VERSION 5.8 ;
BUSBITCHARS "[]" ;
DIVIDERCHAR "/" ;
UNITS
    DATABASE MICRONS 1000 ;
END UNITS

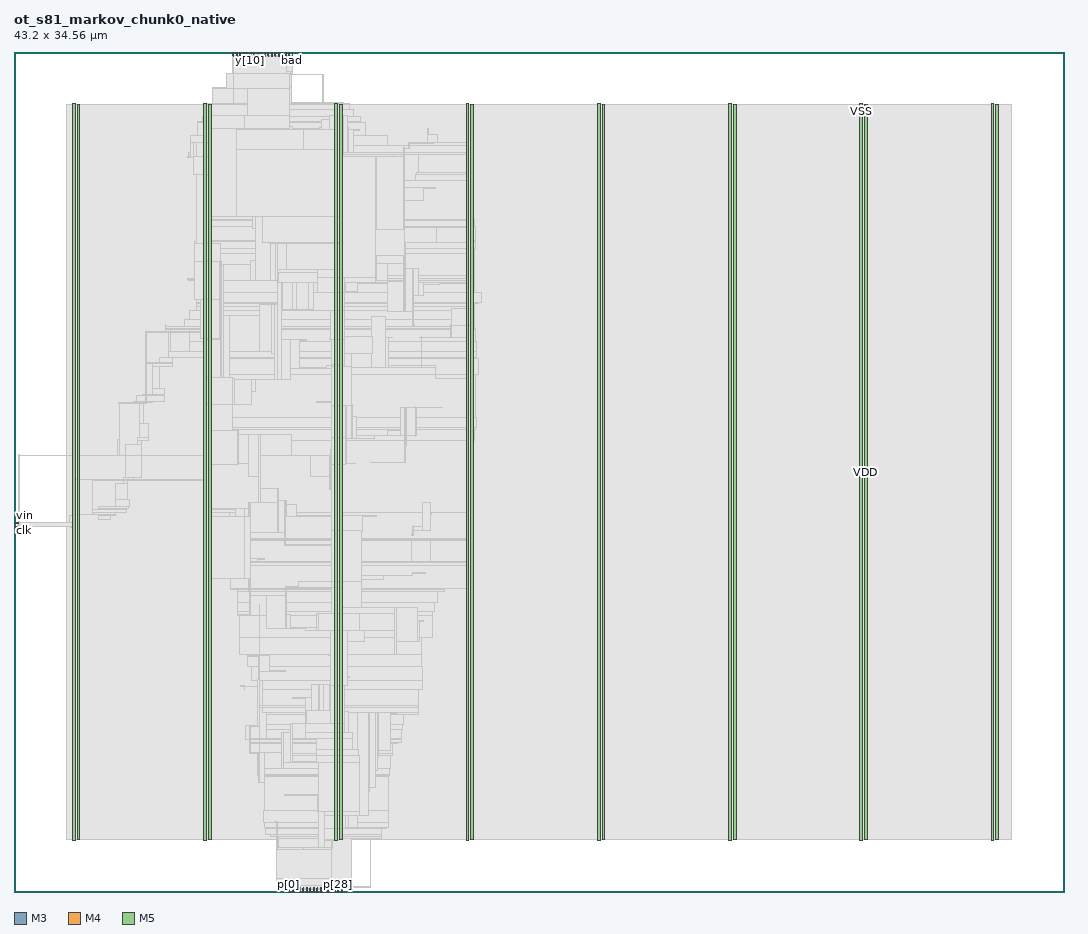
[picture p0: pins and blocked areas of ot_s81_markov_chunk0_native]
MACRO ot_s81_markov_chunk0_native
  FOREIGN ot_s81_markov_chunk0_native 0 0 ;
  CLASS BLOCK ;
  SIZE 43.2 BY 34.56 ;
  PIN bad
    DIRECTION OUTPUT ;
    USE SIGNAL ;
    PORT
      LAYER M3 ;
        RECT  11.448 34.416 11.466 34.56 ;
    END
  END bad
  PIN clk
    DIRECTION INPUT ;
    USE SIGNAL ;
    PORT
      LAYER M4 ;
        RECT  0 14.88 0.192 14.904 ;
    END
  END clk
  PIN p[0]
    DIRECTION INPUT ;
    USE SIGNAL ;
    PORT
      LAYER M3 ;
        RECT  11.304 0 11.322 0.144 ;
    END
  END p[0]
  PIN p[10]
    DIRECTION INPUT ;
    USE SIGNAL ;
    PORT
      LAYER M3 ;
        RECT  12.024 0 12.042 0.144 ;
    END
  END p[10]
  PIN p[11]
    DIRECTION INPUT ;
    USE SIGNAL ;
    PORT
      LAYER M5 ;
        RECT  12.048 0 12.072 0.192 ;
    END
  END p[11]
  PIN p[12]
    DIRECTION INPUT ;
    USE SIGNAL ;
    PORT
      LAYER M3 ;
        RECT  12.168 0 12.186 0.144 ;
    END
  END p[12]
  PIN p[13]
    DIRECTION INPUT ;
    USE SIGNAL ;
    PORT
      LAYER M5 ;
        RECT  12.192 0 12.216 0.192 ;
    END
  END p[13]
  PIN p[14]
    DIRECTION INPUT ;
    USE SIGNAL ;
    PORT
      LAYER M3 ;
        RECT  12.312 0 12.33 0.144 ;
    END
  END p[14]
  PIN p[15]
    DIRECTION INPUT ;
    USE SIGNAL ;
    PORT
      LAYER M5 ;
        RECT  12.336 0 12.36 0.192 ;
    END
  END p[15]
  PIN p[16]
    DIRECTION INPUT ;
    USE SIGNAL ;
    PORT
      LAYER M3 ;
        RECT  12.456 0 12.474 0.144 ;
    END
  END p[16]
  PIN p[17]
    DIRECTION INPUT ;
    USE SIGNAL ;
    PORT
      LAYER M5 ;
        RECT  12.48 0 12.504 0.192 ;
    END
  END p[17]
  PIN p[18]
    DIRECTION INPUT ;
    USE SIGNAL ;
    PORT
      LAYER M3 ;
        RECT  12.6 0 12.618 0.144 ;
    END
  END p[18]
  PIN p[19]
    DIRECTION INPUT ;
    USE SIGNAL ;
    PORT
      LAYER M5 ;
        RECT  12.624 0 12.648 0.192 ;
    END
  END p[19]
  PIN p[1]
    DIRECTION INPUT ;
    USE SIGNAL ;
    PORT
      LAYER M5 ;
        RECT  11.328 0 11.352 0.192 ;
    END
  END p[1]
  PIN p[20]
    DIRECTION INPUT ;
    USE SIGNAL ;
    PORT
      LAYER M3 ;
        RECT  12.744 0 12.762 0.144 ;
    END
  END p[20]
  PIN p[21]
    DIRECTION INPUT ;
    USE SIGNAL ;
    PORT
      LAYER M5 ;
        RECT  12.768 0 12.792 0.192 ;
    END
  END p[21]
  PIN p[22]
    DIRECTION INPUT ;
    USE SIGNAL ;
    PORT
      LAYER M3 ;
        RECT  12.888 0 12.906 0.144 ;
    END
  END p[22]
  PIN p[23]
    DIRECTION INPUT ;
    USE SIGNAL ;
    PORT
      LAYER M5 ;
        RECT  12.912 0 12.936 0.192 ;
    END
  END p[23]
  PIN p[24]
    DIRECTION INPUT ;
    USE SIGNAL ;
    PORT
      LAYER M3 ;
        RECT  13.032 0 13.05 0.144 ;
    END
  END p[24]
  PIN p[25]
    DIRECTION INPUT ;
    USE SIGNAL ;
    PORT
      LAYER M5 ;
        RECT  13.056 0 13.08 0.192 ;
    END
  END p[25]
  PIN p[26]
    DIRECTION INPUT ;
    USE SIGNAL ;
    PORT
      LAYER M3 ;
        RECT  13.176 0 13.194 0.144 ;
    END
  END p[26]
  PIN p[27]
    DIRECTION INPUT ;
    USE SIGNAL ;
    PORT
      LAYER M5 ;
        RECT  13.2 0 13.224 0.192 ;
    END
  END p[27]
  PIN p[28]
    DIRECTION INPUT ;
    USE SIGNAL ;
    PORT
      LAYER M3 ;
        RECT  13.32 0 13.338 0.144 ;
    END
  END p[28]
  PIN p[29]
    DIRECTION INPUT ;
    USE SIGNAL ;
    PORT
      LAYER M5 ;
        RECT  13.344 0 13.368 0.192 ;
    END
  END p[29]
  PIN p[2]
    DIRECTION INPUT ;
    USE SIGNAL ;
    PORT
      LAYER M3 ;
        RECT  11.448 0 11.466 0.144 ;
    END
  END p[2]
  PIN p[30]
    DIRECTION INPUT ;
    USE SIGNAL ;
    PORT
      LAYER M3 ;
        RECT  13.464 0 13.482 0.144 ;
    END
  END p[30]
  PIN p[31]
    DIRECTION INPUT ;
    USE SIGNAL ;
    PORT
      LAYER M5 ;
        RECT  13.488 0 13.512 0.192 ;
    END
  END p[31]
  PIN p[3]
    DIRECTION INPUT ;
    USE SIGNAL ;
    PORT
      LAYER M5 ;
        RECT  11.472 0 11.496 0.192 ;
    END
  END p[3]
  PIN p[4]
    DIRECTION INPUT ;
    USE SIGNAL ;
    PORT
      LAYER M3 ;
        RECT  11.592 0 11.61 0.144 ;
    END
  END p[4]
  PIN p[5]
    DIRECTION INPUT ;
    USE SIGNAL ;
    PORT
      LAYER M5 ;
        RECT  11.616 0 11.64 0.192 ;
    END
  END p[5]
  PIN p[6]
    DIRECTION INPUT ;
    USE SIGNAL ;
    PORT
      LAYER M3 ;
        RECT  11.736 0 11.754 0.144 ;
    END
  END p[6]
  PIN p[7]
    DIRECTION INPUT ;
    USE SIGNAL ;
    PORT
      LAYER M5 ;
        RECT  11.76 0 11.784 0.192 ;
    END
  END p[7]
  PIN p[8]
    DIRECTION INPUT ;
    USE SIGNAL ;
    PORT
      LAYER M3 ;
        RECT  11.88 0 11.898 0.144 ;
    END
  END p[8]
  PIN p[9]
    DIRECTION INPUT ;
    USE SIGNAL ;
    PORT
      LAYER M5 ;
        RECT  11.904 0 11.928 0.192 ;
    END
  END p[9]
  PIN rst_n
    DIRECTION INPUT ;
    USE SIGNAL ;
    PORT
      LAYER M4 ;
        RECT  0 15.024 0.192 15.048 ;
    END
  END rst_n
  PIN vin
    DIRECTION INPUT ;
    USE SIGNAL ;
    PORT
      LAYER M4 ;
        RECT  0 15.168 0.192 15.192 ;
    END
  END vin
  PIN vout
    DIRECTION OUTPUT ;
    USE SIGNAL ;
    PORT
      LAYER M3 ;
        RECT  11.304 34.416 11.322 34.56 ;
    END
  END vout
  PIN y[0]
    DIRECTION OUTPUT ;
    USE SIGNAL ;
    PORT
      LAYER M3 ;
        RECT  9 34.416 9.018 34.56 ;
    END
  END y[0]
  PIN y[10]
    DIRECTION OUTPUT ;
    USE SIGNAL ;
    PORT
      LAYER M3 ;
        RECT  9.72 34.416 9.738 34.56 ;
    END
  END y[10]
  PIN y[11]
    DIRECTION OUTPUT ;
    USE SIGNAL ;
    PORT
      LAYER M5 ;
        RECT  9.744 34.368 9.768 34.56 ;
    END
  END y[11]
  PIN y[12]
    DIRECTION OUTPUT ;
    USE SIGNAL ;
    PORT
      LAYER M3 ;
        RECT  9.864 34.416 9.882 34.56 ;
    END
  END y[12]
  PIN y[13]
    DIRECTION OUTPUT ;
    USE SIGNAL ;
    PORT
      LAYER M5 ;
        RECT  9.888 34.368 9.912 34.56 ;
    END
  END y[13]
  PIN y[14]
    DIRECTION OUTPUT ;
    USE SIGNAL ;
    PORT
      LAYER M3 ;
        RECT  10.008 34.416 10.026 34.56 ;
    END
  END y[14]
  PIN y[15]
    DIRECTION OUTPUT ;
    USE SIGNAL ;
    PORT
      LAYER M5 ;
        RECT  10.032 34.368 10.056 34.56 ;
    END
  END y[15]
  PIN y[16]
    DIRECTION OUTPUT ;
    USE SIGNAL ;
    PORT
      LAYER M3 ;
        RECT  10.152 34.416 10.17 34.56 ;
    END
  END y[16]
  PIN y[17]
    DIRECTION OUTPUT ;
    USE SIGNAL ;
    PORT
      LAYER M5 ;
        RECT  10.176 34.368 10.2 34.56 ;
    END
  END y[17]
  PIN y[18]
    DIRECTION OUTPUT ;
    USE SIGNAL ;
    PORT
      LAYER M3 ;
        RECT  10.296 34.416 10.314 34.56 ;
    END
  END y[18]
  PIN y[19]
    DIRECTION OUTPUT ;
    USE SIGNAL ;
    PORT
      LAYER M5 ;
        RECT  10.32 34.368 10.344 34.56 ;
    END
  END y[19]
  PIN y[1]
    DIRECTION OUTPUT ;
    USE SIGNAL ;
    PORT
      LAYER M5 ;
        RECT  9.024 34.368 9.048 34.56 ;
    END
  END y[1]
  PIN y[20]
    DIRECTION OUTPUT ;
    USE SIGNAL ;
    PORT
      LAYER M3 ;
        RECT  10.44 34.416 10.458 34.56 ;
    END
  END y[20]
  PIN y[21]
    DIRECTION OUTPUT ;
    USE SIGNAL ;
    PORT
      LAYER M5 ;
        RECT  10.464 34.368 10.488 34.56 ;
    END
  END y[21]
  PIN y[22]
    DIRECTION OUTPUT ;
    USE SIGNAL ;
    PORT
      LAYER M3 ;
        RECT  10.584 34.416 10.602 34.56 ;
    END
  END y[22]
  PIN y[23]
    DIRECTION OUTPUT ;
    USE SIGNAL ;
    PORT
      LAYER M5 ;
        RECT  10.608 34.368 10.632 34.56 ;
    END
  END y[23]
  PIN y[24]
    DIRECTION OUTPUT ;
    USE SIGNAL ;
    PORT
      LAYER M3 ;
        RECT  10.728 34.416 10.746 34.56 ;
    END
  END y[24]
  PIN y[25]
    DIRECTION OUTPUT ;
    USE SIGNAL ;
    PORT
      LAYER M5 ;
        RECT  10.752 34.368 10.776 34.56 ;
    END
  END y[25]
  PIN y[26]
    DIRECTION OUTPUT ;
    USE SIGNAL ;
    PORT
      LAYER M3 ;
        RECT  10.872 34.416 10.89 34.56 ;
    END
  END y[26]
  PIN y[27]
    DIRECTION OUTPUT ;
    USE SIGNAL ;
    PORT
      LAYER M5 ;
        RECT  10.896 34.368 10.92 34.56 ;
    END
  END y[27]
  PIN y[28]
    DIRECTION OUTPUT ;
    USE SIGNAL ;
    PORT
      LAYER M3 ;
        RECT  11.016 34.416 11.034 34.56 ;
    END
  END y[28]
  PIN y[29]
    DIRECTION OUTPUT ;
    USE SIGNAL ;
    PORT
      LAYER M5 ;
        RECT  11.04 34.368 11.064 34.56 ;
    END
  END y[29]
  PIN y[2]
    DIRECTION OUTPUT ;
    USE SIGNAL ;
    PORT
      LAYER M3 ;
        RECT  9.144 34.416 9.162 34.56 ;
    END
  END y[2]
  PIN y[30]
    DIRECTION OUTPUT ;
    USE SIGNAL ;
    PORT
      LAYER M3 ;
        RECT  11.16 34.416 11.178 34.56 ;
    END
  END y[30]
  PIN y[31]
    DIRECTION OUTPUT ;
    USE SIGNAL ;
    PORT
      LAYER M5 ;
        RECT  11.184 34.368 11.208 34.56 ;
    END
  END y[31]
  PIN y[3]
    DIRECTION OUTPUT ;
    USE SIGNAL ;
    PORT
      LAYER M5 ;
        RECT  9.168 34.368 9.192 34.56 ;
    END
  END y[3]
  PIN y[4]
    DIRECTION OUTPUT ;
    USE SIGNAL ;
    PORT
      LAYER M3 ;
        RECT  9.288 34.416 9.306 34.56 ;
    END
  END y[4]
  PIN y[5]
    DIRECTION OUTPUT ;
    USE SIGNAL ;
    PORT
      LAYER M5 ;
        RECT  9.312 34.368 9.336 34.56 ;
    END
  END y[5]
  PIN y[6]
    DIRECTION OUTPUT ;
    USE SIGNAL ;
    PORT
      LAYER M3 ;
        RECT  9.432 34.416 9.45 34.56 ;
    END
  END y[6]
  PIN y[7]
    DIRECTION OUTPUT ;
    USE SIGNAL ;
    PORT
      LAYER M5 ;
        RECT  9.456 34.368 9.48 34.56 ;
    END
  END y[7]
  PIN y[8]
    DIRECTION OUTPUT ;
    USE SIGNAL ;
    PORT
      LAYER M3 ;
        RECT  9.576 34.416 9.594 34.56 ;
    END
  END y[8]
  PIN y[9]
    DIRECTION OUTPUT ;
    USE SIGNAL ;
    PORT
      LAYER M5 ;
        RECT  9.6 34.368 9.624 34.56 ;
    END
  END y[9]
  PIN VDD
    DIRECTION INOUT ;
    USE POWER ;
    PORT
      LAYER M5 ;
        RECT  40.392 2.151 40.512 32.409 ;
        RECT  34.992 2.151 35.112 32.409 ;
        RECT  29.592 2.151 29.712 32.409 ;
        RECT  24.192 2.151 24.312 32.409 ;
        RECT  18.792 2.151 18.912 32.409 ;
        RECT  13.392 2.151 13.512 32.409 ;
        RECT  7.992 2.151 8.112 32.409 ;
        RECT  2.592 2.151 2.712 32.409 ;
    END
  END VDD
  PIN VSS
    DIRECTION INOUT ;
    USE GROUND ;
    PORT
      LAYER M5 ;
        RECT  40.2 2.137 40.32 32.423 ;
        RECT  34.8 2.137 34.92 32.423 ;
        RECT  29.4 2.137 29.52 32.423 ;
        RECT  24 2.137 24.12 32.423 ;
        RECT  18.6 2.137 18.72 32.423 ;
        RECT  13.2 2.137 13.32 32.423 ;
        RECT  7.8 2.137 7.92 32.423 ;
        RECT  2.4 2.137 2.52 32.423 ;
    END
  END VSS
  # OT_OBS_CLOSED layer=M5 d_um=1.536 added=33
  OBS
    LAYER RVTN ;
     RECT  2.16 2.16 41.04 2.295 ;
     RECT  2.16 2.565 41.04 2.835 ;
     RECT  2.16 3.105 41.04 3.375 ;
     RECT  2.16 3.645 41.04 3.915 ;
     RECT  2.16 4.185 41.04 4.455 ;
     RECT  2.16 4.725 41.04 4.995 ;
     RECT  2.16 5.265 41.04 5.535 ;
     RECT  2.16 5.805 41.04 6.075 ;
     RECT  2.16 6.345 41.04 6.615 ;
     RECT  2.16 6.885 41.04 7.155 ;
     RECT  2.16 7.425 41.04 7.695 ;
     RECT  2.16 7.965 41.04 8.235 ;
     RECT  2.16 8.505 41.04 8.775 ;
     RECT  2.16 9.045 41.04 9.315 ;
     RECT  2.16 9.585 41.04 9.855 ;
     RECT  2.16 10.125 41.04 10.395 ;
     RECT  2.16 10.665 41.04 10.935 ;
     RECT  2.16 11.205 41.04 11.475 ;
     RECT  2.16 11.745 41.04 12.015 ;
     RECT  2.16 12.285 41.04 12.555 ;
     RECT  2.16 12.825 41.04 13.095 ;
     RECT  2.16 13.365 41.04 13.635 ;
     RECT  2.16 13.905 41.04 14.175 ;
     RECT  2.16 14.445 41.04 14.715 ;
     RECT  2.16 14.985 41.04 15.255 ;
     RECT  2.16 15.525 41.04 15.795 ;
     RECT  2.16 16.065 41.04 16.335 ;
     RECT  2.16 16.605 41.04 16.875 ;
     RECT  2.16 17.145 41.04 17.415 ;
     RECT  2.16 17.685 41.04 17.955 ;
     RECT  2.16 18.225 41.04 18.495 ;
     RECT  2.16 18.765 41.04 19.035 ;
     RECT  2.16 19.305 41.04 19.575 ;
     RECT  2.16 19.845 41.04 20.115 ;
     RECT  2.16 20.385 41.04 20.655 ;
     RECT  2.16 20.925 41.04 21.195 ;
     RECT  2.16 21.465 41.04 21.735 ;
     RECT  2.16 22.005 41.04 22.275 ;
     RECT  2.16 22.545 41.04 22.815 ;
     RECT  2.16 23.085 41.04 23.355 ;
     RECT  2.16 23.625 41.04 23.895 ;
     RECT  2.16 24.165 41.04 24.435 ;
     RECT  2.16 24.705 41.04 24.975 ;
     RECT  2.16 25.245 41.04 25.515 ;
     RECT  2.16 25.785 41.04 26.055 ;
     RECT  2.16 26.325 41.04 26.595 ;
     RECT  2.16 26.865 41.04 27.135 ;
     RECT  2.16 27.405 41.04 27.675 ;
     RECT  2.16 27.945 41.04 28.215 ;
     RECT  2.16 28.485 41.04 28.755 ;
     RECT  2.16 29.025 41.04 29.295 ;
     RECT  2.16 29.565 41.04 29.835 ;
     RECT  2.16 30.105 41.04 30.375 ;
     RECT  2.16 30.645 41.04 30.915 ;
     RECT  2.16 31.185 41.04 31.455 ;
     RECT  2.16 31.725 41.04 31.995 ;
     RECT  2.16 32.265 41.04 32.4 ;
    LAYER RVTP ;
     RECT  2.16 2.295 41.04 2.565 ;
     RECT  2.16 2.835 41.04 3.105 ;
     RECT  2.16 3.375 41.04 3.645 ;
     RECT  2.16 3.915 41.04 4.185 ;
     RECT  2.16 4.455 41.04 4.725 ;
     RECT  2.16 4.995 41.04 5.265 ;
     RECT  2.16 5.535 41.04 5.805 ;
     RECT  2.16 6.075 41.04 6.345 ;
     RECT  2.16 6.615 41.04 6.885 ;
     RECT  2.16 7.155 41.04 7.425 ;
     RECT  2.16 7.695 41.04 7.965 ;
     RECT  2.16 8.235 41.04 8.505 ;
     RECT  2.16 8.775 41.04 9.045 ;
     RECT  2.16 9.315 41.04 9.585 ;
     RECT  2.16 9.855 41.04 10.125 ;
     RECT  2.16 10.395 41.04 10.665 ;
     RECT  2.16 10.935 41.04 11.205 ;
     RECT  2.16 11.475 41.04 11.745 ;
     RECT  2.16 12.015 41.04 12.285 ;
     RECT  2.16 12.555 41.04 12.825 ;
     RECT  2.16 13.095 41.04 13.365 ;
     RECT  2.16 13.635 41.04 13.905 ;
     RECT  2.16 14.175 41.04 14.445 ;
     RECT  2.16 14.715 41.04 14.985 ;
     RECT  2.16 15.255 41.04 15.525 ;
     RECT  2.16 15.795 41.04 16.065 ;
     RECT  2.16 16.335 41.04 16.605 ;
     RECT  2.16 16.875 41.04 17.145 ;
     RECT  2.16 17.415 41.04 17.685 ;
     RECT  2.16 17.955 41.04 18.225 ;
     RECT  2.16 18.495 41.04 18.765 ;
     RECT  2.16 19.035 41.04 19.305 ;
     RECT  2.16 19.575 41.04 19.845 ;
     RECT  2.16 20.115 41.04 20.385 ;
     RECT  2.16 20.655 41.04 20.925 ;
     RECT  2.16 21.195 41.04 21.465 ;
     RECT  2.16 21.735 41.04 22.005 ;
     RECT  2.16 22.275 41.04 22.545 ;
     RECT  2.16 22.815 41.04 23.085 ;
     RECT  2.16 23.355 41.04 23.625 ;
     RECT  2.16 23.895 41.04 24.165 ;
     RECT  2.16 24.435 41.04 24.705 ;
     RECT  2.16 24.975 41.04 25.245 ;
     RECT  2.16 25.515 41.04 25.785 ;
     RECT  2.16 26.055 41.04 26.325 ;
     RECT  2.16 26.595 41.04 26.865 ;
     RECT  2.16 27.135 41.04 27.405 ;
     RECT  2.16 27.675 41.04 27.945 ;
     RECT  2.16 28.215 41.04 28.485 ;
     RECT  2.16 28.755 41.04 29.025 ;
     RECT  2.16 29.295 41.04 29.565 ;
     RECT  2.16 29.835 41.04 30.105 ;
     RECT  2.16 30.375 41.04 30.645 ;
     RECT  2.16 30.915 41.04 31.185 ;
     RECT  2.16 31.455 41.04 31.725 ;
     RECT  2.16 31.995 41.04 32.265 ;
    LAYER M1 ;
     RECT  2.16 2.151 41.04 32.409 ;
    LAYER M2 ;
     RECT  2.16 2.151 11.011 32.409 ;
     RECT  11.011 1.728 11.227 32.409 ;
     RECT  11.155 33.786 11.255 33.804 ;
     RECT  11.227 1.728 11.327 32.49 ;
     RECT  11.327 2.106 12.047 32.49 ;
     RECT  12.047 2.151 12.335 32.49 ;
     RECT  11.443 33.624 12.731 33.642 ;
     RECT  12.883 0.144 12.955 0.162 ;
     RECT  12.335 2.151 13.099 32.454 ;
     RECT  12.955 0.144 13.459 0.198 ;
     RECT  13.459 0.144 13.559 0.234 ;
     RECT  13.351 1.152 13.559 1.17 ;
     RECT  13.099 2.151 13.559 32.49 ;
     RECT  13.559 0.216 13.775 0.234 ;
     RECT  13.559 2.151 13.811 32.454 ;
     RECT  13.811 2.151 41.04 32.409 ;
    LAYER M3 ;
     RECT  11.304 0.108 13.482 0.139 ;
     RECT  11.304 0.139 13.554 0.211 ;
     RECT  11.304 0.211 13.77 0.235 ;
     RECT  11.304 0.235 13.878 0.523 ;
     RECT  10.872 0.523 13.878 2.191 ;
     RECT  14.652 0.187 14.67 2.191 ;
     RECT  10.872 2.191 15.138 2.263 ;
     RECT  10.548 2.263 15.138 2.371 ;
     RECT  2.415 2.143 2.505 2.413 ;
     RECT  7.815 2.143 7.905 2.413 ;
     RECT  18.615 2.143 18.705 2.413 ;
     RECT  24.015 2.143 24.105 2.413 ;
     RECT  29.415 2.143 29.505 2.413 ;
     RECT  34.815 2.143 34.905 2.413 ;
     RECT  40.215 2.143 40.305 2.413 ;
     RECT  10.332 2.371 15.138 2.605 ;
     RECT  10.332 2.605 15.318 2.641 ;
     RECT  10.296 2.641 15.39 2.839 ;
     RECT  10.26 2.839 15.39 3.335 ;
     RECT  10.296 3.335 15.39 4.765 ;
     RECT  10.08 4.765 15.39 4.801 ;
     RECT  10.08 4.801 15.462 4.829 ;
     RECT  10.26 4.829 15.462 5.071 ;
     RECT  10.26 5.071 15.498 5.611 ;
     RECT  10.26 5.611 15.57 5.707 ;
     RECT  9.72 5.707 15.57 6.115 ;
     RECT  9.72 6.115 15.786 6.151 ;
     RECT  9.72 6.151 15.93 6.283 ;
     RECT  9.54 6.283 15.93 6.317 ;
     RECT  10.404 6.317 15.93 6.691 ;
     RECT  9.54 6.317 9.558 6.845 ;
     RECT  10.404 6.691 16.002 6.889 ;
     RECT  10.404 6.889 16.038 7.321 ;
     RECT  10.404 7.321 16.65 7.393 ;
     RECT  10.224 7.393 16.65 7.579 ;
     RECT  10.08 7.579 16.65 7.655 ;
     RECT  10.224 7.655 16.65 8.311 ;
     RECT  9.468 8.311 9.486 8.437 ;
     RECT  9.324 8.437 9.486 8.477 ;
     RECT  10.224 8.311 16.794 8.683 ;
     RECT  9.756 8.683 16.794 9.275 ;
     RECT  9.756 9.275 16.758 9.283 ;
     RECT  9.612 9.283 16.758 9.751 ;
     RECT  9.288 9.751 16.758 10.471 ;
     RECT  9.288 10.471 17.226 11.371 ;
     RECT  9.216 11.371 17.226 11.551 ;
     RECT  9.216 11.551 17.298 11.911 ;
     RECT  9.216 11.911 17.442 12.361 ;
     RECT  9.216 12.361 17.73 12.451 ;
     RECT  8.892 12.451 17.73 12.487 ;
     RECT  18.615 2.413 18.897 12.487 ;
     RECT  7.815 2.413 8.097 13.441 ;
     RECT  8.892 12.487 18.897 13.441 ;
     RECT  7.815 13.441 18.897 13.559 ;
     RECT  8.856 13.559 18.897 13.595 ;
     RECT  8.856 13.595 16.362 14.449 ;
     RECT  17.136 13.595 18.897 14.449 ;
     RECT  7.815 13.559 8.097 14.485 ;
     RECT  8.856 14.449 18.897 14.485 ;
     RECT  7.815 14.485 18.897 14.525 ;
     RECT  2.415 2.413 2.697 15.016 ;
     RECT  2.34 15.016 2.697 15.061 ;
     RECT  2.304 15.061 2.697 15.163 ;
     RECT  2.268 15.163 2.697 15.485 ;
     RECT  3.492 15.331 3.978 15.493 ;
     RECT  2.415 15.485 2.697 15.529 ;
     RECT  3.492 15.493 4.194 15.529 ;
     RECT  2.415 15.529 4.194 15.601 ;
     RECT  7.815 14.525 8.097 15.601 ;
     RECT  8.856 14.525 18.897 15.601 ;
     RECT  2.415 15.601 4.626 15.755 ;
     RECT  3.492 15.755 4.626 15.763 ;
     RECT  3.492 15.763 4.698 15.863 ;
     RECT  4.176 15.863 4.698 15.871 ;
     RECT  4.176 15.871 4.77 16.133 ;
     RECT  4.176 16.133 4.662 16.799 ;
     RECT  4.5 16.799 4.662 16.951 ;
     RECT  3.708 16.915 3.726 16.973 ;
     RECT  4.5 16.951 4.914 17.041 ;
     RECT  4.5 17.041 5.238 17.069 ;
     RECT  4.572 17.069 5.238 18.419 ;
     RECT  5.076 18.419 5.238 18.571 ;
     RECT  7.815 15.601 18.897 18.571 ;
     RECT  4.32 18.565 4.338 18.605 ;
     RECT  5.076 18.571 5.526 18.689 ;
     RECT  7.815 18.571 18.954 19.039 ;
     RECT  7.815 19.039 18.99 19.111 ;
     RECT  5.148 18.689 5.526 19.265 ;
     RECT  7.815 19.111 19.026 19.535 ;
     RECT  5.148 19.265 5.31 20.107 ;
     RECT  4.896 20.107 5.31 20.155 ;
     RECT  4.896 20.155 5.706 20.183 ;
     RECT  5.04 20.183 5.706 20.191 ;
     RECT  5.04 20.191 6.174 20.417 ;
     RECT  5.292 20.417 6.174 20.489 ;
     RECT  5.688 20.489 6.174 20.723 ;
     RECT  7.815 19.535 18.99 21.271 ;
     RECT  5.688 20.723 5.994 21.631 ;
     RECT  5.688 21.631 6.534 21.739 ;
     RECT  5.436 21.739 6.534 21.803 ;
     RECT  7.815 21.271 19.098 21.965 ;
     RECT  5.976 21.803 6.534 21.973 ;
     RECT  7.815 21.965 19.026 21.973 ;
     RECT  5.976 21.973 19.026 22.001 ;
     RECT  6.336 22.001 19.026 22.235 ;
     RECT  7.2 22.235 19.026 22.649 ;
     RECT  6.336 22.235 6.426 23.035 ;
     RECT  6.228 23.035 6.426 23.161 ;
     RECT  7.2 22.649 18.99 23.161 ;
     RECT  6.228 23.161 18.99 23.189 ;
     RECT  6.228 23.189 18.954 23.279 ;
     RECT  6.228 23.279 6.246 23.351 ;
     RECT  7.02 23.279 18.954 23.549 ;
     RECT  7.2 23.549 18.954 23.927 ;
     RECT  7.488 23.927 18.954 24.089 ;
     RECT  7.524 24.089 18.954 24.205 ;
     RECT  7.524 24.205 19.098 24.241 ;
     RECT  7.524 24.241 19.242 24.665 ;
     RECT  7.524 24.665 18.954 25.177 ;
     RECT  7.164 25.177 18.954 25.229 ;
     RECT  7.668 25.229 18.954 25.349 ;
     RECT  7.815 25.349 18.954 26.257 ;
     RECT  7.488 26.257 18.954 26.491 ;
     RECT  7.488 26.491 18.99 26.765 ;
     RECT  7.56 26.765 18.99 26.789 ;
     RECT  7.815 26.789 18.99 27.365 ;
     RECT  7.815 27.365 18.954 27.643 ;
     RECT  7.596 27.643 18.954 27.671 ;
     RECT  7.596 27.671 18.897 29.291 ;
     RECT  16.524 29.291 18.897 29.525 ;
     RECT  16.56 29.525 18.897 29.597 ;
     RECT  7.596 29.291 15.606 29.851 ;
     RECT  7.38 29.851 15.606 30.235 ;
     RECT  7.164 30.235 15.606 30.343 ;
     RECT  16.632 29.597 18.897 30.343 ;
     RECT  7.164 30.343 18.897 30.443 ;
     RECT  7.272 30.443 18.897 30.713 ;
     RECT  16.236 30.713 18.897 30.839 ;
     RECT  16.236 30.839 16.254 30.845 ;
     RECT  7.272 30.713 15.354 31.109 ;
     RECT  7.272 31.109 15.138 31.145 ;
     RECT  17.028 30.839 17.406 31.181 ;
     RECT  17.028 31.181 17.046 31.415 ;
     RECT  7.56 31.145 14.454 31.649 ;
     RECT  7.56 31.649 14.238 31.721 ;
     RECT  7.74 31.721 14.238 31.919 ;
     RECT  2.415 15.755 2.697 32.147 ;
     RECT  18.615 30.839 18.897 32.147 ;
     RECT  24.015 2.413 24.297 32.147 ;
     RECT  29.415 2.413 29.697 32.147 ;
     RECT  34.815 2.413 35.097 32.147 ;
     RECT  40.215 2.413 40.497 32.147 ;
     RECT  7.815 31.919 13.95 32.189 ;
     RECT  2.415 32.147 2.505 32.417 ;
     RECT  7.815 32.189 13.806 32.417 ;
     RECT  18.615 32.147 18.705 32.417 ;
     RECT  24.015 32.147 24.105 32.417 ;
     RECT  29.415 32.147 29.505 32.417 ;
     RECT  34.815 32.147 34.905 32.417 ;
     RECT  40.215 32.147 40.305 32.417 ;
     RECT  8.172 32.417 13.806 32.459 ;
     RECT  12.312 32.459 13.554 32.495 ;
     RECT  8.172 32.459 11.43 33.101 ;
     RECT  8.748 33.101 11.43 33.619 ;
     RECT  12.708 32.495 12.726 33.647 ;
     RECT  8.748 33.619 11.466 33.677 ;
     RECT  9 33.677 11.466 34.428 ;
    LAYER M4 ;
     RECT  0.156 14.88 0.227 15.192 ;
     RECT  0.227 15.024 2.408 15.192 ;
     RECT  0.181 17.952 2.408 17.976 ;
     RECT  2.408 2.148 2.512 32.412 ;
     RECT  2.512 2.418 2.704 32.142 ;
     RECT  2.704 15.552 3.251 15.576 ;
     RECT  2.704 17.952 4.268 17.976 ;
     RECT  4.268 17.952 4.355 18.6 ;
     RECT  4.309 20.112 5.459 20.136 ;
     RECT  5.413 21.744 5.5 21.768 ;
     RECT  7.153 30.24 7.261 30.264 ;
     RECT  7.261 30.24 7.369 30.84 ;
     RECT  7.369 29.856 7.381 30.84 ;
     RECT  7.153 25.2 7.429 25.224 ;
     RECT  7.429 26.64 7.436 26.664 ;
     RECT  5.413 23.04 7.669 23.064 ;
     RECT  2.704 16.944 7.808 16.968 ;
     RECT  4.355 17.952 7.808 17.976 ;
     RECT  7.669 22.8 7.808 23.064 ;
     RECT  7.429 24.384 7.808 25.224 ;
     RECT  7.436 26.64 7.808 26.76 ;
     RECT  7.621 28.464 7.808 28.488 ;
     RECT  7.381 29.52 7.808 30.84 ;
     RECT  7.808 2.148 7.912 32.412 ;
     RECT  7.912 2.418 8.104 32.412 ;
     RECT  8.104 28.464 8.165 31.176 ;
     RECT  8.104 20.064 8.489 26.664 ;
     RECT  8.489 20.064 8.524 25.944 ;
     RECT  8.524 20.064 8.633 25.8 ;
     RECT  8.161 33.072 8.737 33.096 ;
     RECT  8.633 20.064 8.885 23.736 ;
     RECT  8.165 28.464 8.957 30.168 ;
     RECT  8.885 20.064 9.052 21.144 ;
     RECT  8.104 14.496 9.097 14.52 ;
     RECT  8.104 15.744 9.097 15.768 ;
     RECT  8.957 28.464 9.116 28.488 ;
     RECT  8.165 31.152 9.157 31.176 ;
     RECT  8.104 17.952 9.164 18.216 ;
     RECT  9.164 17.952 9.205 18.984 ;
     RECT  8.957 29.568 9.205 30.168 ;
     RECT  9.157 31.152 9.205 31.416 ;
     RECT  9.205 17.616 9.251 18.984 ;
     RECT  9.205 29.568 9.389 31.416 ;
     RECT  9.389 29.616 9.457 31.416 ;
     RECT  9.205 12.912 9.493 12.936 ;
     RECT  9.097 14.496 9.493 15.768 ;
     RECT  8.737 33.072 9.533 33.672 ;
     RECT  9.493 12.912 9.637 15.768 ;
     RECT  9.251 17.616 9.637 18.84 ;
     RECT  9.637 12.912 9.644 16.008 ;
     RECT  9.205 11.376 9.673 11.4 ;
     RECT  9.644 12.384 9.673 16.008 ;
     RECT  9.673 11.376 9.677 16.008 ;
     RECT  9.529 6.288 9.709 6.84 ;
     RECT  9.677 11.376 9.731 12.408 ;
     RECT  9.677 13.584 9.731 16.008 ;
     RECT  8.633 25.152 9.745 25.8 ;
     RECT  9.709 5.712 9.749 6.84 ;
     RECT  9.052 20.064 9.785 21.096 ;
     RECT  9.116 27.792 9.817 28.488 ;
     RECT  9.745 25.152 9.925 25.992 ;
     RECT  9.817 27.312 9.925 28.488 ;
     RECT  9.457 29.616 9.925 31.944 ;
     RECT  9.785 20.592 9.929 21.096 ;
     RECT  9.749 6.816 10.021 6.84 ;
     RECT  9.313 8.448 10.021 8.472 ;
     RECT  9.749 5.712 10.028 5.736 ;
     RECT  9.731 13.584 10.037 13.704 ;
     RECT  10.021 6.816 10.067 8.712 ;
     RECT  10.028 4.8 10.069 5.736 ;
     RECT  10.067 8.688 10.069 8.712 ;
     RECT  9.601 9.696 10.069 9.72 ;
     RECT  9.731 15.024 10.069 16.008 ;
     RECT  9.637 17.088 10.069 18.84 ;
     RECT  8.885 22.224 10.105 23.736 ;
     RECT  10.069 8.688 10.109 9.72 ;
     RECT  10.069 15.024 10.145 18.84 ;
     RECT  10.069 4.512 10.325 5.736 ;
     RECT  10.037 13.68 10.325 13.704 ;
     RECT  9.533 33.648 10.385 33.672 ;
     RECT  9.731 11.376 10.393 12.216 ;
     RECT  10.109 9.072 10.505 9.72 ;
     RECT  9.925 25.152 10.549 28.488 ;
     RECT  9.925 29.616 10.549 31.992 ;
     RECT  10.105 22.224 10.609 24.168 ;
     RECT  9.929 21.072 10.717 21.096 ;
     RECT  10.609 22.176 10.717 24.168 ;
     RECT  10.549 25.152 10.741 31.992 ;
     RECT  10.741 25.152 10.829 32.376 ;
     RECT  10.717 2.88 10.835 2.904 ;
     RECT  10.145 15.024 10.837 16.584 ;
     RECT  10.717 21.072 10.837 24.168 ;
     RECT  10.829 25.152 10.837 31.944 ;
     RECT  10.789 0.144 10.861 0.168 ;
     RECT  10.837 14.784 10.883 16.584 ;
     RECT  10.325 5.088 11.005 5.736 ;
     RECT  10.067 7.584 11.009 7.608 ;
     RECT  10.837 21.072 11.009 31.944 ;
     RECT  11.009 23.952 11.027 31.944 ;
     RECT  10.385 33.648 11.041 33.768 ;
     RECT  11.005 5.088 11.081 6.552 ;
     RECT  10.883 14.784 11.149 16.104 ;
     RECT  10.393 10.848 11.185 12.216 ;
     RECT  10.505 9.072 11.189 9.096 ;
     RECT  11.149 14.256 11.189 16.104 ;
     RECT  11.041 33.648 11.219 33.816 ;
     RECT  11.185 10.848 11.225 12.552 ;
     RECT  11.189 15.456 11.225 16.104 ;
     RECT  11.219 33.648 11.363 33.768 ;
     RECT  11.081 5.328 11.365 6.552 ;
     RECT  11.225 10.848 11.369 11.4 ;
     RECT  11.009 21.072 11.369 22.728 ;
     RECT  10.145 17.952 11.405 18.84 ;
     RECT  10.861 0.144 11.437 0.552 ;
     RECT  11.365 5.328 11.441 6.936 ;
     RECT  11.363 33.744 11.441 33.768 ;
     RECT  11.437 0.144 11.477 0.6 ;
     RECT  11.027 23.952 11.477 31.512 ;
     RECT  11.477 0.192 11.521 0.6 ;
     RECT  11.225 15.456 11.621 15.96 ;
     RECT  11.477 23.952 11.629 31.416 ;
     RECT  11.521 0.192 11.651 0.552 ;
     RECT  11.617 1.776 11.689 1.8 ;
     RECT  11.225 12.528 11.725 12.552 ;
     RECT  11.369 21.552 11.729 22.728 ;
     RECT  11.369 10.848 11.977 10.872 ;
     RECT  11.441 6.336 11.989 6.936 ;
     RECT  11.473 7.968 11.989 7.992 ;
     RECT  11.729 22.704 12.017 22.728 ;
     RECT  11.629 23.952 12.125 25.416 ;
     RECT  11.405 17.952 12.193 17.976 ;
     RECT  11.989 6.336 12.229 7.992 ;
     RECT  11.977 10.752 12.445 10.872 ;
     RECT  11.149 3.984 12.476 4.008 ;
     RECT  11.441 5.328 12.517 5.352 ;
     RECT  12.229 6.336 12.517 8.52 ;
     RECT  12.517 5.328 12.553 8.52 ;
     RECT  11.629 26.592 12.553 31.416 ;
     RECT  12.553 26.592 12.661 31.464 ;
     RECT  11.689 1.728 12.697 1.8 ;
     RECT  11.651 0.528 12.733 0.552 ;
     RECT  12.553 5.28 12.733 8.52 ;
     RECT  12.476 3.312 12.805 4.008 ;
     RECT  11.729 21.552 12.877 21.576 ;
     RECT  12.697 1.728 12.947 2.328 ;
     RECT  12.805 3.312 12.985 4.056 ;
     RECT  12.733 5.184 12.985 8.52 ;
     RECT  12.193 17.088 12.985 17.976 ;
     RECT  12.661 26.592 12.985 31.8 ;
     RECT  12.985 16.56 13.004 17.976 ;
     RECT  12.947 1.776 13.091 2.328 ;
     RECT  13.091 2.148 13.093 2.328 ;
     RECT  12.985 3.312 13.093 8.52 ;
     RECT  12.877 21.552 13.093 21.672 ;
     RECT  12.997 22.752 13.093 22.776 ;
     RECT  12.445 20.16 13.129 20.184 ;
     RECT  13.093 21.552 13.129 22.776 ;
     RECT  12.733 0.288 13.189 0.552 ;
     RECT  13.093 2.148 13.208 8.52 ;
     RECT  12.956 9.744 13.208 9.768 ;
     RECT  12.445 10.752 13.208 11.448 ;
     RECT  11.725 12.528 13.208 12.792 ;
     RECT  11.189 14.256 13.208 14.28 ;
     RECT  11.621 15.456 13.208 15.48 ;
     RECT  13.004 16.56 13.208 18.216 ;
     RECT  13.129 19.536 13.208 22.776 ;
     RECT  12.125 23.952 13.208 25.272 ;
     RECT  12.985 26.592 13.208 31.944 ;
     RECT  13.208 2.148 13.312 32.412 ;
     RECT  13.189 0.192 13.379 0.552 ;
     RECT  13.312 2.352 13.421 32.142 ;
     RECT  13.421 2.418 13.504 32.142 ;
     RECT  13.504 30.336 13.565 31.944 ;
     RECT  13.504 24.72 13.619 25.272 ;
     RECT  13.504 17.616 13.667 20.616 ;
     RECT  13.504 27.888 13.673 29.256 ;
     RECT  13.565 30.432 13.709 31.944 ;
     RECT  13.504 8.496 13.715 11.448 ;
     RECT  13.504 2.64 13.745 7.416 ;
     RECT  13.709 30.432 13.781 31.464 ;
     RECT  13.715 8.832 13.817 8.856 ;
     RECT  13.379 0.192 13.889 0.264 ;
     RECT  13.667 18.672 13.889 20.616 ;
     RECT  13.889 18.672 13.907 20.04 ;
     RECT  13.504 26.784 13.925 26.808 ;
     RECT  13.673 27.888 13.961 29.064 ;
     RECT  13.781 30.432 13.961 31.368 ;
     RECT  13.667 17.616 14.033 17.64 ;
     RECT  13.907 18.672 14.105 19.56 ;
     RECT  13.745 2.64 14.141 7.368 ;
     RECT  13.619 24.72 14.141 25.128 ;
     RECT  13.961 31.344 14.213 31.368 ;
     RECT  13.961 27.888 14.285 28.776 ;
     RECT  13.504 12.768 14.291 13.032 ;
     RECT  13.504 14.832 14.321 15.48 ;
     RECT  13.715 10.32 14.429 11.448 ;
     RECT  14.141 3.168 14.573 7.368 ;
     RECT  14.573 4.128 14.645 7.368 ;
     RECT  13.889 0.192 14.681 0.216 ;
     RECT  13.504 21.6 14.713 22.248 ;
     RECT  14.105 18.672 14.825 18.792 ;
     RECT  14.645 4.32 14.861 7.368 ;
     RECT  14.321 15.456 14.933 15.48 ;
     RECT  14.857 30.24 14.941 30.264 ;
     RECT  14.861 4.992 14.969 7.368 ;
     RECT  14.969 5.568 15.005 7.368 ;
     RECT  14.291 12.864 15.221 13.032 ;
     RECT  14.713 21.6 15.293 23.688 ;
     RECT  14.141 25.056 15.349 25.128 ;
     RECT  14.825 18.768 15.361 18.792 ;
     RECT  15.349 25.008 15.361 25.128 ;
     RECT  15.145 26.208 15.361 26.232 ;
     RECT  15.293 21.6 15.401 22.824 ;
     RECT  15.005 5.808 15.473 7.368 ;
     RECT  15.361 26.208 15.493 26.28 ;
     RECT  15.473 6.624 15.509 7.368 ;
     RECT  15.401 22.8 15.581 22.824 ;
     RECT  15.145 11.664 15.613 11.688 ;
     RECT  15.613 10.944 15.637 11.688 ;
     RECT  15.509 7.344 15.725 7.368 ;
     RECT  15.637 9.792 15.725 11.688 ;
     RECT  15.361 18.768 15.901 18.984 ;
     RECT  15.493 26.208 15.977 27.24 ;
     RECT  15.361 23.904 16.021 25.128 ;
     RECT  15.977 26.208 16.021 26.856 ;
     RECT  14.285 28.464 16.021 28.488 ;
     RECT  16.021 23.904 16.067 26.856 ;
     RECT  14.677 17.664 16.069 17.688 ;
     RECT  15.901 18.768 16.069 19.944 ;
     RECT  16.069 17.664 16.115 19.944 ;
     RECT  16.067 23.904 16.121 26.76 ;
     RECT  16.115 18.384 16.157 19.944 ;
     RECT  16.021 30.576 16.225 30.6 ;
     RECT  16.225 30.576 16.265 30.84 ;
     RECT  15.221 13.008 16.405 13.032 ;
     RECT  16.369 14.688 16.405 14.712 ;
     RECT  16.121 23.904 16.405 25.656 ;
     RECT  16.405 13.008 16.409 13.128 ;
     RECT  16.405 23.328 16.451 25.656 ;
     RECT  16.405 14.688 16.453 15.048 ;
     RECT  16.451 23.328 16.492 23.352 ;
     RECT  16.157 18.768 16.547 19.944 ;
     RECT  15.725 10.32 16.589 11.688 ;
     RECT  16.451 24.528 16.625 25.656 ;
     RECT  16.589 10.32 16.697 11.16 ;
     RECT  16.453 14.88 16.801 15.048 ;
     RECT  16.697 11.136 16.841 11.16 ;
     RECT  16.625 24.528 16.841 25.08 ;
     RECT  16.021 28.464 16.841 28.968 ;
     RECT  16.409 13.104 16.949 13.128 ;
     RECT  16.801 14.88 17.129 16.008 ;
     RECT  17.129 15.552 17.165 15.576 ;
     RECT  16.265 30.816 17.273 30.84 ;
     RECT  15.401 21.6 17.341 21.672 ;
     RECT  17.341 21.12 17.345 21.672 ;
     RECT  16.841 28.944 17.345 28.968 ;
     RECT  16.121 26.736 17.365 26.76 ;
     RECT  17.365 26.736 17.411 27.336 ;
     RECT  16.841 25.008 17.489 25.08 ;
     RECT  16.547 19.92 17.633 19.944 ;
     RECT  16.693 22.8 17.948 22.824 ;
     RECT  17.948 22.8 17.989 23.352 ;
     RECT  17.345 21.12 18.608 21.144 ;
     RECT  17.989 22.8 18.608 23.976 ;
     RECT  17.489 25.056 18.608 25.08 ;
     RECT  17.411 27.312 18.608 27.336 ;
     RECT  18.608 2.148 18.712 32.412 ;
     RECT  18.712 2.418 18.904 32.142 ;
     RECT  24.008 2.148 24.112 32.412 ;
     RECT  24.112 2.418 24.304 32.142 ;
     RECT  29.408 2.148 29.512 32.412 ;
     RECT  29.512 2.418 29.704 32.142 ;
     RECT  34.808 2.148 34.912 32.412 ;
     RECT  34.912 2.418 35.104 32.142 ;
     RECT  40.208 2.148 40.312 32.412 ;
     RECT  40.312 2.418 40.504 32.142 ;
    LAYER M5 ;
     RECT  10.8 0.133 10.824 0.144 ;
     RECT  10.8 0.144 13.512 0.275 ;
     RECT  10.8 0.275 13.368 0.563 ;
     RECT  10.8 0.563 13.08 1.763 ;
     RECT  11.904 1.763 13.08 1.811 ;
     RECT  12.768 1.811 13.08 2.137 ;
     RECT  2.4 2.137 2.52 2.151 ;
     RECT  7.8 2.137 7.92 2.151 ;
     RECT  12.768 2.137 13.32 2.151 ;
     RECT  18.6 2.137 18.72 2.151 ;
     RECT  24 2.137 24.12 2.151 ;
     RECT  29.4 2.137 29.52 2.151 ;
     RECT  34.8 2.137 34.92 2.151 ;
     RECT  40.2 2.137 40.32 2.151 ;
     RECT  12.768 2.151 13.512 2.629 ;
     RECT  10.8 1.763 10.824 2.915 ;
     RECT  12.768 2.629 13.656 3.157 ;
     RECT  12.768 3.157 14.232 3.301 ;
     RECT  12.528 3.301 14.232 5.317 ;
     RECT  12.432 5.317 14.232 5.603 ;
     RECT  12.432 5.603 14.184 5.843 ;
     RECT  12.432 5.843 13.944 6.325 ;
     RECT  12 6.325 13.944 6.563 ;
     RECT  10.08 4.501 10.104 6.805 ;
     RECT  12 6.563 13.608 6.947 ;
     RECT  12 6.947 12.024 7.475 ;
     RECT  13.008 6.947 13.608 8.485 ;
     RECT  10.032 6.805 10.104 8.723 ;
     RECT  13.008 8.485 13.704 10.741 ;
     RECT  12.528 10.741 14.232 11.459 ;
     RECT  15.648 9.781 15.672 11.699 ;
     RECT  10.08 8.723 10.104 11.843 ;
     RECT  13.2 11.459 13.512 12.517 ;
     RECT  13.056 12.517 13.512 12.757 ;
     RECT  9.696 12.373 9.72 12.901 ;
     RECT  13.056 12.757 14.28 14.867 ;
     RECT  16.416 14.677 16.44 15.059 ;
     RECT  9.504 12.901 9.72 15.443 ;
     RECT  2.4 2.151 2.712 15.541 ;
     RECT  9.696 15.443 9.72 16.019 ;
     RECT  10.848 14.773 10.872 16.595 ;
     RECT  2.4 15.541 3.24 16.979 ;
     RECT  13.056 14.867 13.512 17.605 ;
     RECT  0.192 14.869 0.216 17.987 ;
     RECT  16.08 17.653 16.104 18.419 ;
     RECT  13.056 17.605 13.656 18.707 ;
     RECT  9.216 17.605 9.24 18.995 ;
     RECT  16.512 18.757 16.536 19.955 ;
     RECT  13.056 18.707 13.512 20.005 ;
     RECT  7.8 2.151 8.112 20.053 ;
     RECT  4.32 18.565 4.344 20.147 ;
     RECT  7.8 20.053 9 21.155 ;
     RECT  13.056 20.005 13.896 21.635 ;
     RECT  13.056 21.635 13.608 21.683 ;
     RECT  7.8 21.155 8.112 22.741 ;
     RECT  13.2 21.683 13.608 22.741 ;
     RECT  7.8 22.741 8.472 22.789 ;
     RECT  14.736 22.165 14.76 22.835 ;
     RECT  16.752 21.637 16.776 22.835 ;
     RECT  5.424 20.101 5.448 23.075 ;
     RECT  18.6 2.151 18.912 23.317 ;
     RECT  16.416 23.317 16.44 23.939 ;
     RECT  13.008 22.741 13.608 23.941 ;
     RECT  18 23.317 18.912 23.987 ;
     RECT  7.68 22.789 8.472 24.373 ;
     RECT  12.336 23.941 13.608 24.659 ;
     RECT  15.36 24.997 15.384 25.093 ;
     RECT  14.88 25.093 15.384 25.139 ;
     RECT  12.48 24.659 13.608 25.283 ;
     RECT  10.848 25.093 10.872 25.475 ;
     RECT  12.48 25.283 13.512 25.621 ;
     RECT  7.44 24.373 8.472 25.955 ;
     RECT  14.88 25.139 14.904 26.197 ;
     RECT  16.032 25.861 16.056 26.197 ;
     RECT  7.44 25.955 8.112 26.675 ;
     RECT  11.232 25.621 13.512 26.677 ;
     RECT  10.512 26.677 13.512 26.725 ;
     RECT  14.88 26.197 16.056 27.251 ;
     RECT  17.376 26.725 17.4 27.347 ;
     RECT  10.224 26.725 13.512 27.781 ;
     RECT  7.488 26.675 8.112 29.509 ;
     RECT  7.392 29.509 8.112 30.275 ;
     RECT  14.88 27.251 14.904 30.275 ;
     RECT  9.168 27.781 13.512 30.563 ;
     RECT  16.032 27.251 16.056 30.611 ;
     RECT  7.488 30.275 8.112 30.851 ;
     RECT  9.168 30.563 11.928 31.379 ;
     RECT  9.168 31.379 11.352 31.427 ;
     RECT  9.504 31.427 11.352 31.955 ;
     RECT  2.4 16.979 2.712 32.409 ;
     RECT  7.8 30.851 8.112 32.409 ;
     RECT  13.2 30.563 13.512 32.409 ;
     RECT  18.6 23.987 18.912 32.409 ;
     RECT  24 2.151 24.312 32.409 ;
     RECT  29.4 2.151 29.712 32.409 ;
     RECT  34.8 2.151 35.112 32.409 ;
     RECT  40.2 2.151 40.512 32.409 ;
     RECT  2.4 32.409 2.52 32.423 ;
     RECT  7.8 32.409 7.92 32.423 ;
     RECT  13.2 32.409 13.32 32.423 ;
     RECT  18.6 32.409 18.72 32.423 ;
     RECT  24 32.409 24.12 32.423 ;
     RECT  29.4 32.409 29.52 32.423 ;
     RECT  34.8 32.409 34.92 32.423 ;
     RECT  40.2 32.409 40.32 32.423 ;
     RECT  9.6 31.955 11.352 33.061 ;
     RECT  9.024 33.061 11.352 33.683 ;
     RECT  9.024 33.683 11.208 34.384 ;
     RECT  10.824 1.763 11.904 1.811 ;
     RECT  12.528 1.811 12.768 3.301 ;
     RECT  12.024 6.947 13.008 7.475 ;
     RECT  14.232 10.741 15.648 11.459 ;
     RECT  13.056 11.459 13.2 12.517 ;
     RECT  13.512 11.459 15.648 11.699 ;
     RECT  13.512 11.699 14.28 12.757 ;
     RECT  8.112 12.901 9.504 15.443 ;
     RECT  9.72 14.773 10.848 16.019 ;
     RECT  8.112 17.605 9.216 18.995 ;
     RECT  13.512 18.707 13.656 20.005 ;
     RECT  8.112 18.995 9 20.053 ;
     RECT  4.344 20.101 5.424 20.147 ;
     RECT  13.608 21.635 13.896 22.165 ;
     RECT  13.056 21.683 13.2 22.741 ;
     RECT  13.608 22.165 14.736 22.835 ;
     RECT  12.336 24.659 12.48 25.093 ;
     RECT  10.872 25.093 12.48 25.475 ;
     RECT  13.608 25.093 14.88 25.283 ;
     RECT  14.904 25.139 15.384 25.861 ;
     RECT  13.512 25.283 14.88 30.275 ;
     RECT  10.848 25.475 12.48 25.621 ;
     RECT  10.848 25.621 11.232 26.677 ;
     RECT  14.904 25.861 16.032 26.197 ;
     RECT  16.056 26.725 17.376 27.347 ;
     RECT  17.4 26.725 18.6 27.347 ;
     RECT  14.904 27.251 16.032 30.275 ;
     RECT  8.112 27.781 9.168 31.427 ;
     RECT  11.928 30.563 13.2 31.379 ;
     RECT  8.112 31.427 9.504 31.955 ;
     RECT  8.112 31.955 9.6 32.409 ;
     RECT  7.92 32.409 9.6 32.423 ;
     RECT  9.024 32.423 9.6 33.061 ;
  END
END ot_s81_markov_chunk0_native
END LIBRARY
